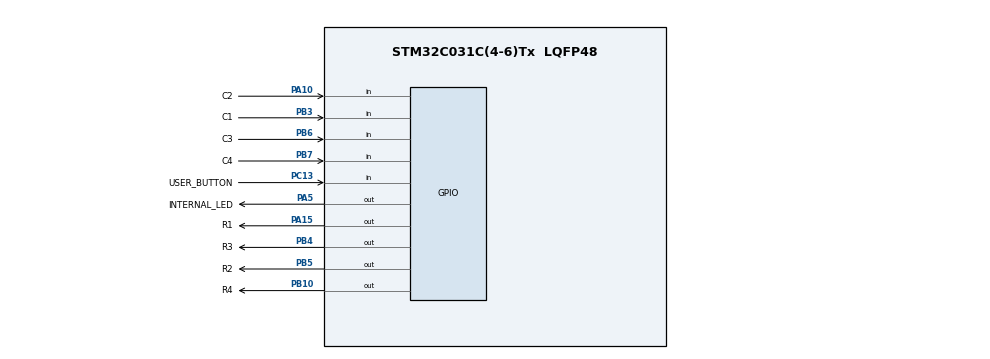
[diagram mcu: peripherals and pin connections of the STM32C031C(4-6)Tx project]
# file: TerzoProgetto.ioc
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Mcu.Family=STM32C0
Mcu.Name=STM32C031C(4-6)Tx
Mcu.Package=LQFP48
PA10.GPIO_Label=C2
PA10.GPIO_PuPd=GPIO_PULLDOWN
PA10.Signal=GPIO_Input
PA13.GPIO_Label=DEBUG_SWDIO
PA13.Signal=DEBUG_SWDIO
PA14-BOOT0.GPIO_Label=DEBUG_SWCLK
PA14-BOOT0.Signal=DEBUG_SWCLK
PA15.GPIO_Label=R1
PA15.GPIO_PuPd=GPIO_NOPULL
PA15.Signal=GPIO_Output
PA2.GPIO_Label=VCP_USART2_TX
PA2.Signal=USART2_TX
PA3.GPIO_Label=VCP_USART2_RX
PA3.Signal=USART2_RX
PA5.GPIO_Label=INTERNAL_LED
PA5.GPIO_PuPd=GPIO_NOPULL
PA5.Signal=GPIO_Output
PB10.GPIO_Label=R4
PB10.Signal=GPIO_Output
PB3.GPIO_Label=C1
PB3.GPIO_PuPd=GPIO_PULLDOWN
PB3.Signal=GPIO_Input
PB4.GPIO_Label=R3
PB4.Signal=GPIO_Output
PB5.GPIO_Label=R2
PB5.Signal=GPIO_Output
PB6.GPIO_Label=C3
PB6.GPIO_PuPd=GPIO_PULLDOWN
PB6.Signal=GPIO_Input
PB7.GPIO_Label=C4
PB7.GPIO_PuPd=GPIO_PULLDOWN
PB7.Signal=GPIO_Input
PC13.GPIO_Label=USER_BUTTON
PC13.Signal=GPIO_Input
PC14-OSCX_IN\ (PC14).GPIO_Label=RCC_OSCX_IN
PC14-OSCX_IN\ (PC14).Mode=LSE-External-Oscillator
PC14-OSCX_IN\ (PC14).Signal=RCC_OSCX_IN
PC15-OSCX_OUT\ (PC15).GPIO_Label=RCC_OSCX_OUT
PC15-OSCX_OUT\ (PC15).Mode=LSE-External-Oscillator
PC15-OSCX_OUT\ (PC15).Signal=RCC_OSCX_OUT
PF0-OSC_IN\ (PF0).GPIO_Label=RCC_OSC_IN
PF0-OSC_IN\ (PF0).Mode=HSE-External-Oscillator
PF0-OSC_IN\ (PF0).Signal=RCC_OSC_IN
PF1-OSC_OUT\ (PF1).GPIO_Label=RCC_OSC_OUT
PF1-OSC_OUT\ (PF1).Mode=HSE-External-Oscillator
PF1-OSC_OUT\ (PF1).Signal=RCC_OSC_OUT
ProjectManager.HeapSize=0x200
ProjectManager.StackSize=0x400
ProjectManager.TargetToolchain=STM32CubeIDE
RCC.ADCFreq_Value=48000000
RCC.AHBFreq_Value=48000000
RCC.CortexFreq_Value=48000000
RCC.EXTERNAL_CLOCK_VALUE=12288000
RCC.HCLKFreq_Value=48000000
RCC.HSE_VALUE=48000000
RCC.HSISYSCLKDivider=RCC_HSI_DIV1
RCC.HSI_VALUE=48000000
RCC.SYSCLKFreq_VALUE=48000000
RCC.SYSCLKSource=RCC_SYSCLKSOURCE_HSE
board=NUCLEO-C031C6

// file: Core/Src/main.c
/* USER CODE BEGIN Header */
/**
  ******************************************************************************
  * @file           : main.c
  * @brief          : Main program body
  ******************************************************************************
  */
 /* USER CODE END Header */

#include "main.h"

void SystemClock_Config(void);
static void MX_GPIO_Init(void);

/* USER CODE BEGIN PV */

// Righe (OUTPUT)
#define R1_GPIO GPIOA
#define R1_Pin  GPIO_PIN_15

#define R2_GPIO GPIOB
#define R2_Pin  GPIO_PIN_5

#define R3_GPIO GPIOB
#define R3_Pin  GPIO_PIN_4

#define R4_GPIO GPIOB
#define R4_Pin  GPIO_PIN_10

// Colonne (INPUT)
#define C1_GPIO GPIOB
#define C1_Pin  GPIO_PIN_3

#define C2_GPIO GPIOA
#define C2_Pin  GPIO_PIN_10

#define C3_GPIO GPIOB
#define C3_Pin  GPIO_PIN_6

#define C4_GPIO GPIOB
#define C4_Pin  GPIO_PIN_7

// LED binari
#define LED0_GPIO GPIOA
#define LED0_Pin  GPIO_PIN_0

#define LED1_GPIO GPIOA
#define LED1_Pin  GPIO_PIN_1

#define LED2_GPIO GPIOA
#define LED2_Pin  GPIO_PIN_2

#define LED3_GPIO GPIOA
#define LED3_Pin  GPIO_PIN_3

// LED interno
#define LED_INT_GPIO GPIOA
#define LED_INT_Pin  GPIO_PIN_5

/* USER CODE END PV */

/* USER CODE BEGIN PFP */
int readKeypad(void);
void displayBinary(int value);
/* USER CODE END PFP */

int main(void)
{
  HAL_Init();
  SystemClock_Config();
  MX_GPIO_Init();

  while (1)
  {
      int key = readKeypad();

      if (key != -1)
      {
          HAL_GPIO_WritePin(LED_INT_GPIO, LED_INT_Pin, GPIO_PIN_SET);
          displayBinary(key);
          HAL_Delay(200);
      }
      else
      {
          HAL_GPIO_WritePin(LED_INT_GPIO, LED_INT_Pin, GPIO_PIN_RESET);
      }
  }
}

/* USER CODE BEGIN 4 */

int readKeypad()
{
    GPIO_TypeDef* rowGPIO[4] = {R1_GPIO, R2_GPIO, R3_GPIO, R4_GPIO};
    uint16_t rowPin[4]       = {R1_Pin, R2_Pin, R3_Pin, R4_Pin};

    GPIO_TypeDef* colGPIO[4] = {C1_GPIO, C2_GPIO, C3_GPIO, C4_GPIO};
    uint16_t colPin[4]       = {C1_Pin, C2_Pin, C3_Pin, C4_Pin};

    // Porta tutte le righe LOW
    HAL_GPIO_WritePin(R1_GPIO, R1_Pin, GPIO_PIN_RESET);
    HAL_GPIO_WritePin(R2_GPIO, R2_Pin, GPIO_PIN_RESET);
    HAL_GPIO_WritePin(R3_GPIO, R3_Pin, GPIO_PIN_RESET);
    HAL_GPIO_WritePin(R4_GPIO, R4_Pin, GPIO_PIN_RESET);

    for (int r = 0; r < 4; r++)
    {
        HAL_GPIO_WritePin(rowGPIO[r], rowPin[r], GPIO_PIN_SET);
        HAL_Delay(2);

        for (int c = 0; c < 4; c++)
        {
            if (HAL_GPIO_ReadPin(colGPIO[c], colPin[c]) == GPIO_PIN_SET)
            {
                HAL_GPIO_WritePin(rowGPIO[r], rowPin[r], GPIO_PIN_RESET);
                return r * 4 + c;
            }
        }

        HAL_GPIO_WritePin(rowGPIO[r], rowPin[r], GPIO_PIN_RESET);
    }

    return -1;
}

void displayBinary(int value)
{
    HAL_GPIO_WritePin(LED0_GPIO, LED0_Pin, (value & 0x01) ? GPIO_PIN_SET : GPIO_PIN_RESET);
    HAL_GPIO_WritePin(LED1_GPIO, LED1_Pin, (value & 0x02) ? GPIO_PIN_SET : GPIO_PIN_RESET);
    HAL_GPIO_WritePin(LED2_GPIO, LED2_Pin, (value & 0x04) ? GPIO_PIN_SET : GPIO_PIN_RESET);
    HAL_GPIO_WritePin(LED3_GPIO, LED3_Pin, (value & 0x08) ? GPIO_PIN_SET : GPIO_PIN_RESET);
}

/* USER CODE END 4 */

void SystemClock_Config(void)
{
  RCC_OscInitTypeDef RCC_OscInitStruct = {0};
  RCC_ClkInitTypeDef RCC_ClkInitStruct = {0};

  RCC_OscInitStruct.OscillatorType = RCC_OSCILLATORTYPE_HSI;
  RCC_OscInitStruct.HSIState = RCC_HSI_ON;
  RCC_OscInitStruct.HSIDiv = RCC_HSI_DIV1;
  RCC_OscInitStruct.HSICalibrationValue = RCC_HSICALIBRATION_DEFAULT;

  HAL_RCC_OscConfig(&RCC_OscInitStruct);

  RCC_ClkInitStruct.ClockType = RCC_CLOCKTYPE_HCLK | RCC_CLOCKTYPE_SYSCLK | RCC_CLOCKTYPE_PCLK1;
  RCC_ClkInitStruct.SYSCLKSource = RCC_SYSCLKSOURCE_HSI;
  RCC_ClkInitStruct.AHBCLKDivider = RCC_SYSCLK_DIV1;
  RCC_ClkInitStruct.APB1CLKDivider = RCC_APB1_DIV1;

  HAL_RCC_ClockConfig(&RCC_ClkInitStruct, FLASH_LATENCY_0);
}

static void MX_GPIO_Init(void)
{
  GPIO_InitTypeDef GPIO_InitStruct = {0};

  __HAL_RCC_GPIOA_CLK_ENABLE();
  __HAL_RCC_GPIOB_CLK_ENABLE();

  // OUTPUT: R1–R4
  GPIO_InitStruct.Mode = GPIO_MODE_OUTPUT_PP;
  GPIO_InitStruct.Pull = GPIO_NOPULL;
  GPIO_InitStruct.Speed = GPIO_SPEED_FREQ_LOW;

  GPIO_InitStruct.Pin = R1_Pin;
  HAL_GPIO_Init(R1_GPIO, &GPIO_InitStruct);

  GPIO_InitStruct.Pin = R2_Pin;
  HAL_GPIO_Init(R2_GPIO, &GPIO_InitStruct);

  GPIO_InitStruct.Pin = R3_Pin;
  HAL_GPIO_Init(R3_GPIO, &GPIO_InitStruct);

  GPIO_InitStruct.Pin = R4_Pin;
  HAL_GPIO_Init(R4_GPIO, &GPIO_InitStruct);

  // OUTPUT: LED binari + LED interno
  GPIO_InitStruct.Pin = LED0_Pin | LED1_Pin | LED2_Pin | LED3_Pin | LED_INT_Pin;
  HAL_GPIO_Init(GPIOA, &GPIO_InitStruct);

  // INPUT: colonne con pull-down
  GPIO_InitStruct.Mode = GPIO_MODE_INPUT;
  GPIO_InitStruct.Pull = GPIO_PULLDOWN;

  GPIO_InitStruct.Pin = C1_Pin;
  HAL_GPIO_Init(C1_GPIO, &GPIO_InitStruct);

  GPIO_InitStruct.Pin = C2_Pin;
  HAL_GPIO_Init(C2_GPIO, &GPIO_InitStruct);

  GPIO_InitStruct.Pin = C3_Pin;
  HAL_GPIO_Init(C3_GPIO, &GPIO_InitStruct);

  GPIO_InitStruct.Pin = C4_Pin;
  HAL_GPIO_Init(C4_GPIO, &GPIO_InitStruct);
}
